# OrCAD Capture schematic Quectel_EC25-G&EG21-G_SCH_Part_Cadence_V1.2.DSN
size A1

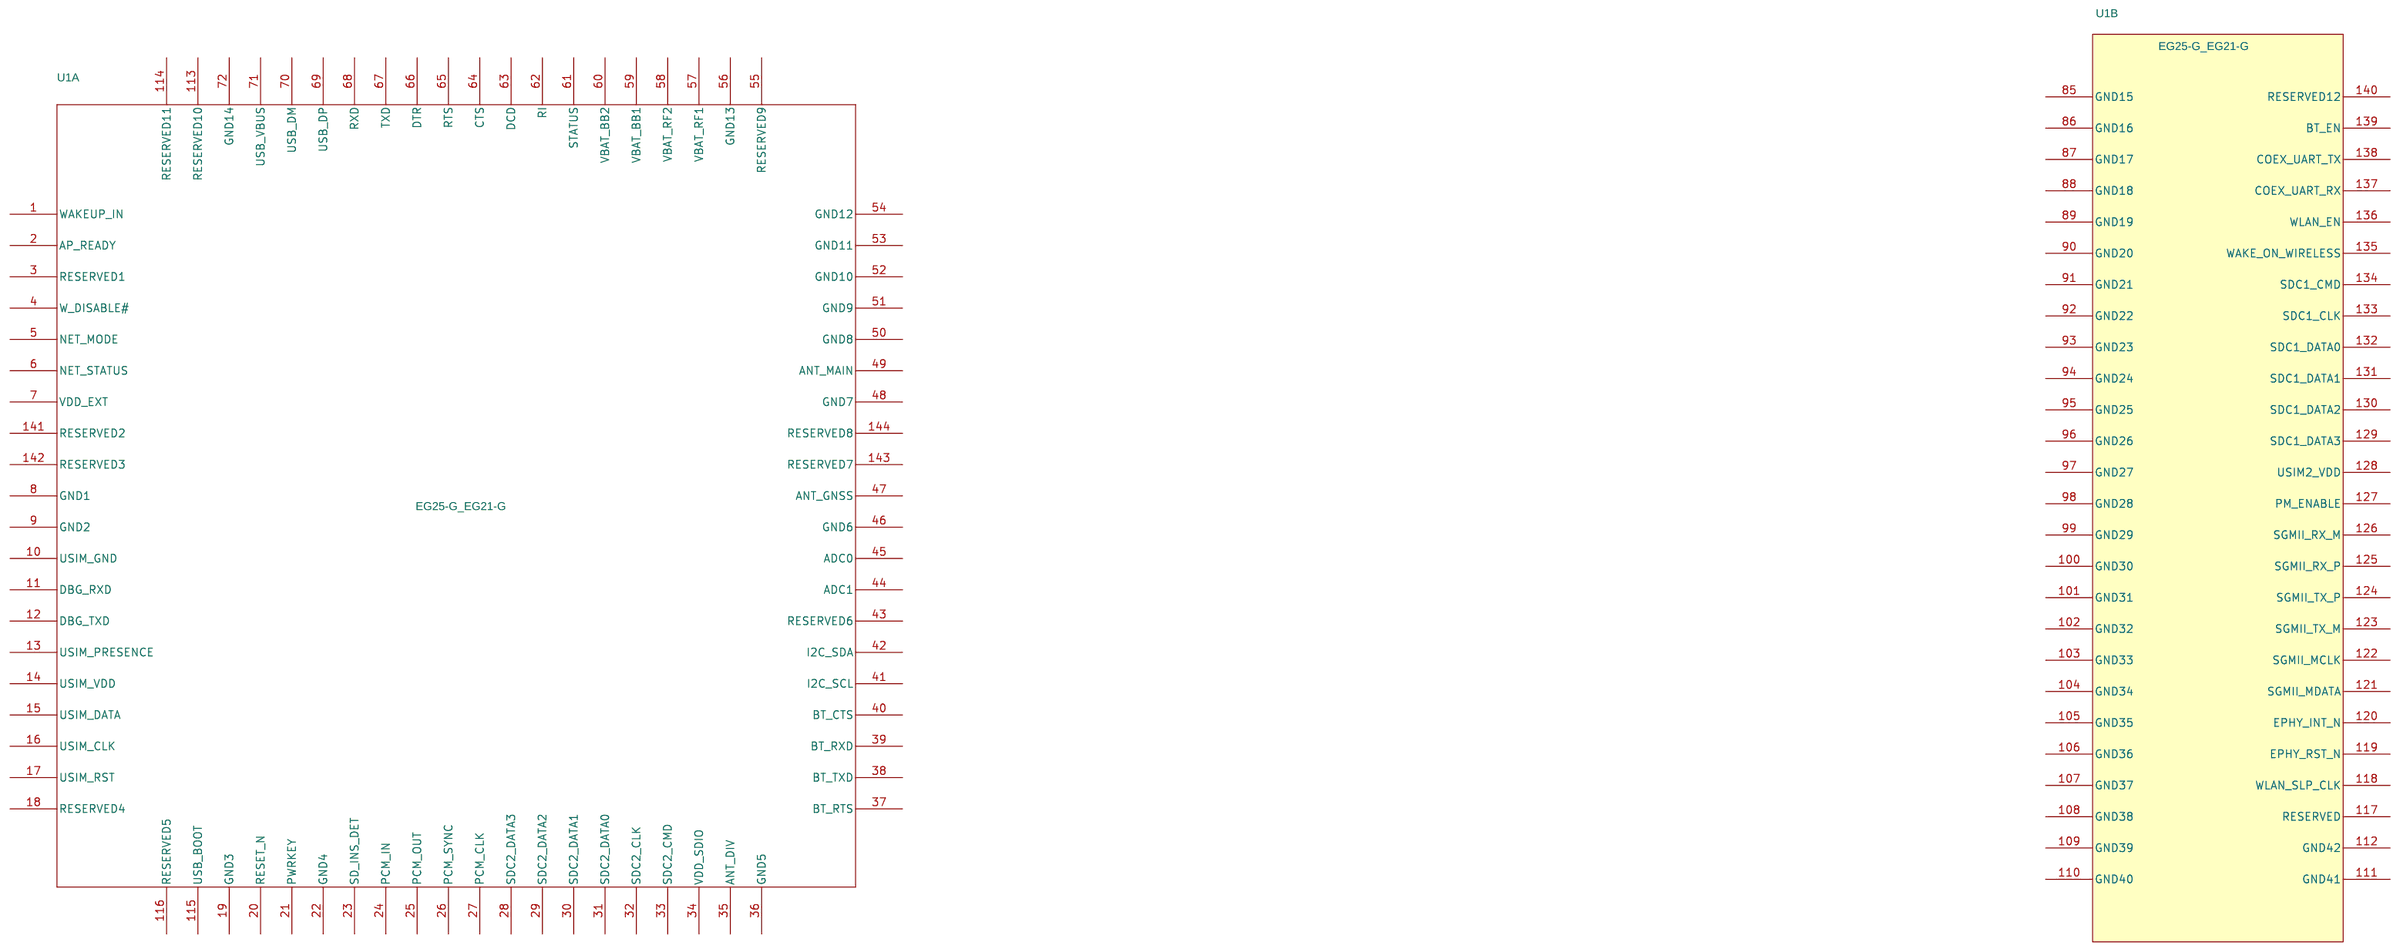
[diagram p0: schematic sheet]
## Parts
U1  EG25-G_EG21-G  [EG25-G_EG21-G]  (sections A,B)

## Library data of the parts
U1 = EG25-G_EG21-G

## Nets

Not connected (* = marked no-connect by the designer): U1 1(WAKEUP_IN) 2(AP_READY) 3(RESERVED1) 4(W_DISABLE#) 5(NET_MODE) 6(NET_STATUS) 7(VDD_EXT) 8(GND1) 9(GND2) 10(USIM_GND) 11(DBG_RXD) 12(DBG_TXD) 13(USIM_PRESENCE) 14(USIM_VDD) 15(USIM_DATA) 16(USIM_CLK) 17(USIM_RST) 18(RESERVED4) 19(GND3) 20(RESET_N) 21(PWRKEY) 22(GND4) 23(SD_INS_DET) 24(PCM_IN) 25(PCM_OUT) 26(PCM_SYNC) 27(PCM_CLK) 28(SDC2_DATA3) 29(SDC2_DATA2) 30(SDC2_DATA1) 31(SDC2_DATA0) 32(SDC2_CLK) 33(SDC2_CMD) 34(VDD_SDIO) 35(ANT_DIV) 36(GND5) 37(BT_RTS) 38(BT_TXD) 39(BT_RXD) 40(BT_CTS) 41(I2C_SCL) 42(I2C_SDA) 43(RESERVED6) 44(ADC1) 45(ADC0) 46(GND6) 47(ANT_GNSS) 48(GND7) 49(ANT_MAIN) 50(GND8) 51(GND9) 52(GND10) 53(GND11) 54(GND12) 55(RESERVED9) 56(GND13) 57(VBAT_RF1) 58(VBAT_RF2) 59(VBAT_BB1) 60(VBAT_BB2) 61(STATUS) 62(RI) 63(DCD) 64(CTS) 65(RTS) 66(DTR) 67(TXD) 68(RXD) 69(USB_DP) 70(USB_DM) 71(USB_VBUS) 72(GND14) 85(GND15) 86(GND16) 87(GND17) 88(GND18) 89(GND19) 90(GND20) 91(GND21) 92(GND22) 93(GND23) 94(GND24) 95(GND25) 96(GND26) 97(GND27) 98(GND28) 99(GND29) 100(GND30) 101(GND31) 102(GND32) 103(GND33) 104(GND34) 105(GND35) 106(GND36) 107(GND37) 108(GND38) 109(GND39) 110(GND40) 111(GND41) 112(GND42) 113(RESERVED10) 114(RESERVED11) 115(USB_BOOT) 116(RESERVED5) 117(RESERVED) 118(WLAN_SLP_CLK) 119(EPHY_RST_N) 120(EPHY_INT_N) 121(SGMII_MDATA) 122(SGMII_MCLK) 123(SGMII_TX_M) 124(SGMII_TX_P) 125(SGMII_RX_P) 126(SGMII_RX_M) 127(PM_ENABLE) 128(USIM2_VDD) 129(SDC1_DATA3) 130(SDC1_DATA2) 131(SDC1_DATA1) 132(SDC1_DATA0) 133(SDC1_CLK) 134(SDC1_CMD) 135(WAKE_ON_WIRELESS) 136(WLAN_EN) 137(COEX_UART_RX) 138(COEX_UART_TX) 139(BT_EN) 140(RESERVED12) 141(RESERVED2) 142(RESERVED3) 143(RESERVED7) 144(RESERVED8)
